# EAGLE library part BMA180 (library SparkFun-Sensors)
3-axis, 14-bit SPI/I2C accelerometer. Range 1/1.5/2/3/4/8/16g.

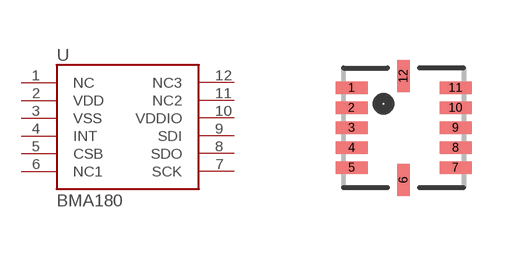
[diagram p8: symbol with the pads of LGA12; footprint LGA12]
Designator prefix -

## BMA180  [LGA12]
1  NC
2  VDD
3  VSS
4  INT
5  CSB
6  NC1
7  SCK
8  SDO
9  SDI
10  VDDIO
11  NC2
12  NC3

## Footprint LGA12 (pad centres in mm)
smd 0.8 x 0.32: 1 -1.3,1; 2 -1.3,0.5; 3 -1.3,0; 4 -1.3,-0.5; 5 -1.3,-1; 7 1.3,-1; 8 1.3,-0.5; 9 1.3,0; 10 1.3,0.5; 11 1.3,1
smd 0.32 x 0.8: 6 0,-1.3; 12 0,1.3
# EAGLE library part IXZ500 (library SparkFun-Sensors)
IXZ-500 Dual Axis (X/Z) Gyro

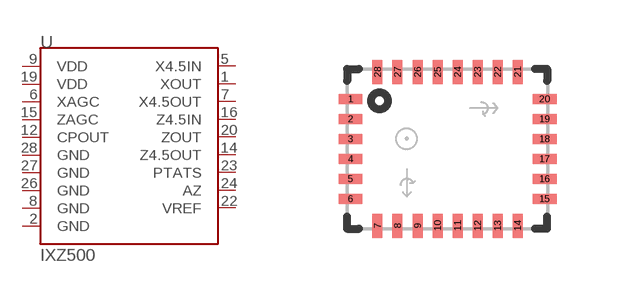
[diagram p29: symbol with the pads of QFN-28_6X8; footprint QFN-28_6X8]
Designator prefix U

## IXZ500SMD  [QFN-28_6X8]
1  XOUT
2  GND
5  X4.5IN
6  XAGC
7  X4.5OUT
8  GND
9  VDD
12  CPOUT
14  Z4.5OUT
15  ZAGC
16  Z4.5IN
19  VDD
20  ZOUT
22  VREF
23  PTATS
24  AZ
26  GND
27  GND
28  GND

## Footprint QFN-28_6X8 (pad centres in mm)
QFN package with a 6x8 pin configuration.
smd 0.6 x 0.25: 1 -2.417,1.25; 2 -2.417,0.75; 3 -2.417,0.25; 4 -2.417,-0.25; 5 -2.417,-0.75; 6 -2.417,-1.25; 15 2.433,-1.25; 16 2.433,-0.75; 17 2.433,-0.25; 18 2.433,0.25; 19 2.433,0.75; 20 2.433,1.25
smd 0.25 x 0.6: 7 -1.742,-1.925; 8 -1.242,-1.925; 9 -0.742,-1.925; 10 -0.242,-1.925; 11 0.258,-1.925; 12 0.758,-1.925; 13 1.258,-1.925; 14 1.758,-1.925; 21 1.758,1.925; 22 1.258,1.925; 23 0.758,1.925; 24 0.258,1.925; 25 -0.242,1.925; 26 -0.742,1.925; 27 -1.242,1.925; 28 -1.742,1.925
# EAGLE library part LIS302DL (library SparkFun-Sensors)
3-axis I2C/SPI 2/8g accelerometer

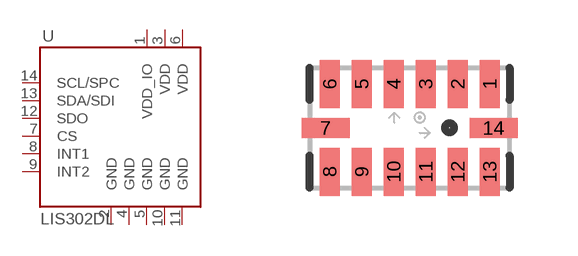
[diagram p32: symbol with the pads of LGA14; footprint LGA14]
Designator prefix -

## LIS302DL  [LGA14]
1  VDD_IO  pwr
2  GND  pwr
3  VDD  pwr
4  GND  pwr
5  GND  pwr
6  VDD  pwr
7  CS  in
8  INT1  out
9  INT2  out
10  GND  pwr
11  GND  pwr
12  SDO  out
13  SDA/SDI  in
14  SCL/SPC  in

## Footprint LGA14 (pad centres in mm)
smd 0.5 x 1.2: 1 2,1.1; 2 1.2,1.1; 3 0.4,1.1; 4 -0.4,1.1; 5 -1.2,1.1; 6 -2,1.1; 8 -2,-1.1; 9 -1.2,-1.1; 10 -0.4,-1.1; 11 0.4,-1.1; 12 1.2,-1.1; 13 2,-1.1
smd 1.2 x 0.5: 7 -2.1,0; 14 2.1,0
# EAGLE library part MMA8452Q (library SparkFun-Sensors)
MMA8452Q 3-Axis, 12/8-bit Digital Accelerometer Supply Voltage: 1.6-3.6V Range: +/- 2g, 4g, 8g Interface: I2C, 12-bit and 8-bit ODR: 1.56 Hz - 800 Hz Package: QFN-16 http://cache.freescale.com/files/sensors/doc/data_sheet/MMA8452Q.pdf

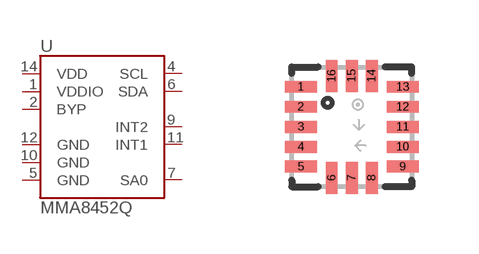
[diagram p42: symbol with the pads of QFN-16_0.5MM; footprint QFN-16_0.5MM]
Designator prefix U

## MMA8452Q (PROD_ID: IC-10769)  [QFN-16_0.5MM]
1  VDDIO
2  BYP
4  SCL
5  GND
6  SDA
7  SA0
9  INT2
10  GND
11  INT1
12  GND
14  VDD

## Footprint QFN-16_0.5MM (pad centres in mm)
QFN-16 0.5mm Pitch 3 x 3mm Outline 16-pin Used on the MMA8452Q accelerometer Unproven Layout in accordance with App note AN4077 http://cache.freescale.com/files/sensors/doc/app_note/AN4077.pdf
smd 0.8 x 0.3: 1 -1.275,1; 2 -1.275,0.5; 3 -1.275,0; 4 -1.275,-0.5; 5 -1.275,-1; 9 1.275,-1; 10 1.275,-0.5; 11 1.275,0; 12 1.275,0.5; 13 1.275,1
smd 0.3 x 0.8: 6 -0.5,-1.275; 7 0,-1.275; 8 0.5,-1.275; 14 0.5,1.275; 15 0,1.275; 16 -0.5,1.275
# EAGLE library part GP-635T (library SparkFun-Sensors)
Footprint and symbol for a generic 6-pin JST GPS module connector.

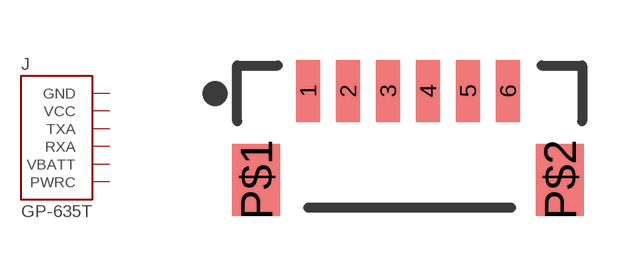
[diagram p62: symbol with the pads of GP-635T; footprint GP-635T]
Designator prefix J

## GP-635TSMD (PROD_ID: CONN-08249)  [GP-635T]
1  GND  pwr
2  VCC  pwr
3  TXA  out
4  RXA  in
5  VBATT  pwr
6  PWRC  in

## Footprint GP-635T (pad centres in mm)
smd 0.6 x 1.55: 1 -2.54,1.27; 2 -1.54,1.27; 3 -0.54,1.27; 4 0.46,1.27; 5 1.46,1.27; 6 2.46,1.27
smd 1.2 x 1.8: P$1 -3.84,-0.955; P$2 3.76,-0.955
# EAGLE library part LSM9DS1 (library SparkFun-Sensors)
LSM9DS1 3D accelerometer, gyroscope & magnetometer The LSM9DS1 is a system-in-package featuring a 3D digital linear acceleration sensor, a 3D digital angular rate sensor, and a 3D digital magnetic sensor. The LSM9DS1 has a linear acceleration full scale of ±2g/±4g/±8/±16 g, a magnetic field full scale of ±4/±8/±12/±16 gauss and an angular rate of ±245/±500/±2000 dps. The LSM9DS1 includes an I2 C serial bus interface supporting standard and fast mode (100 kHz and 400 kHz) and an SPI serial standard interface. Magnetic, accelerometer and gyroscope sensing can be enabled or set in power-down mode separately for smart power management. The LSM9DS1 is available in a plastic land grid array package (LGA) and it is guaranteed to operate over an extended temperature range from -40 °C to +85 °C.

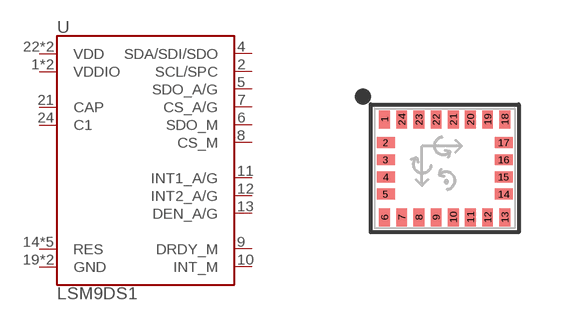
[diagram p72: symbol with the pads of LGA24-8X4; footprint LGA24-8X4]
Designator prefix U

## LSM9DS1 (PROD_ID: IC-12536)  [LGA24-8X4]
1  VDDIO
2  SCL/SPC
3  VDDIO
4  SDA/SDI/SDO
5  SDO_A/G
6  SDO_M
7  CS_A/G
8  CS_M
9  DRDY_M
10  INT_M
11  INT1_A/G
12  INT2_A/G
13  DEN_A/G
14  RES
15  RES
16  RES
17  RES
18  RES
19  GND
20  GND
21  CAP
22  VDD
23  VDD
24  C1

## Footprint LGA24-8X4 (pad centres in mm)
24-pin LGA 8x4 pins Footprint: 3.5 x 3mm Used by: LSM9DS1 Unproven
smd 0.27 x 0.45: 1 -1.505,1.225; 6 -1.505,-1.225; 7 -1.075,-1.225; 8 -0.645,-1.225; 9 -0.215,-1.225; 10 0.215,-1.225; 11 0.645,-1.225; 12 1.075,-1.225; 13 1.505,-1.225; 18 1.505,1.225; 19 1.075,1.225; 20 0.645,1.225; 21 0.215,1.225; 22 -0.215,1.225; 23 -0.645,1.225; 24 -1.075,1.225
smd 0.45 x 0.27: 2 -1.475,0.645; 3 -1.475,0.215; 4 -1.475,-0.215; 5 -1.475,-0.645; 14 1.475,-0.645; 15 1.475,-0.215; 16 1.475,0.215; 17 1.475,0.645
